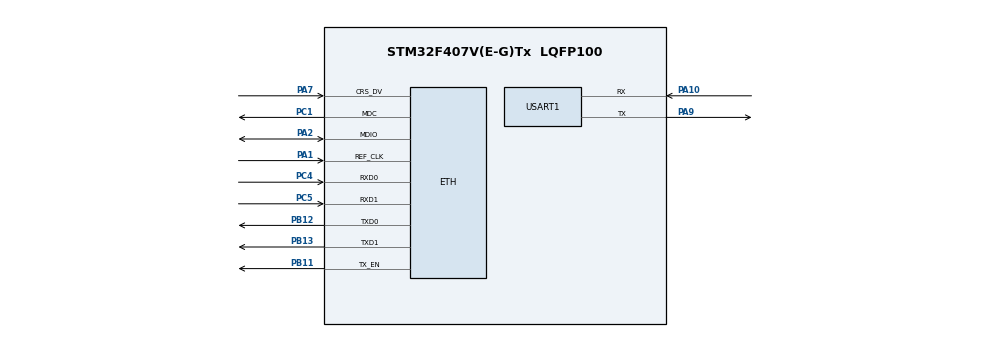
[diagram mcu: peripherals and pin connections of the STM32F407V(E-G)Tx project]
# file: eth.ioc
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ETH.MediaInterface=HAL_ETH_RMII_MODE
FREERTOS.Tasks01=defaultTask,24,128,StartDefaultTask,Default,NULL,Dynamic,NULL,NULL
LWIP.LWIP_HTTPD=1
LWIP.Version=v2.1.2_Cube
Mcu.Family=STM32F4
Mcu.Name=STM32F407V(E-G)Tx
Mcu.Package=LQFP100
NVIC.ETH_IRQn=true\:5\:0\:true\:false\:true\:true\:true\:true\:true
NVIC.PriorityGroup=NVIC_PRIORITYGROUP_4
NVIC.TIM6_DAC_IRQn=true\:15\:0\:false\:false\:true\:false\:false\:true\:true
NVIC.TimeBase=TIM6_DAC_IRQn
NVIC.TimeBaseIP=TIM6
NVIC.USART1_IRQn=true\:5\:0\:false\:false\:true\:true\:true\:true\:true
PA1.Mode=RMII
PA1.Signal=ETH_REF_CLK
PA10.Mode=Asynchronous
PA10.Signal=USART1_RX
PA13.Mode=Serial_Wire
PA13.Signal=SYS_JTMS-SWDIO
PA14.Mode=Serial_Wire
PA14.Signal=SYS_JTCK-SWCLK
PA2.Mode=RMII
PA2.Signal=ETH_MDIO
PA7.Mode=RMII
PA7.Signal=ETH_CRS_DV
PA9.Mode=Asynchronous
PA9.Signal=USART1_TX
PB11.Mode=RMII
PB11.Signal=ETH_TX_EN
PB12.Mode=RMII
PB12.Signal=ETH_TXD0
PB13.Mode=RMII
PB13.Signal=ETH_TXD1
PC1.Mode=RMII
PC1.Signal=ETH_MDC
PC4.Mode=RMII
PC4.Signal=ETH_RXD0
PC5.Mode=RMII
PC5.Signal=ETH_RXD1
PH0-OSC_IN.Mode=HSE-External-Oscillator
PH0-OSC_IN.Signal=RCC_OSC_IN
PH1-OSC_OUT.Mode=HSE-External-Oscillator
PH1-OSC_OUT.Signal=RCC_OSC_OUT
ProjectManager.HeapSize=0x200
ProjectManager.StackSize=0x400
ProjectManager.TargetToolchain=MDK-ARM V5.32
RCC.48MHZClocksFreq_Value=84000000
RCC.AHBFreq_Value=168000000
RCC.APB1CLKDivider=RCC_HCLK_DIV4
RCC.APB1Freq_Value=42000000
RCC.APB1TimFreq_Value=84000000
RCC.APB2CLKDivider=RCC_HCLK_DIV2
RCC.APB2Freq_Value=84000000
RCC.APB2TimFreq_Value=168000000
RCC.CortexFreq_Value=168000000
RCC.HCLKFreq_Value=168000000
RCC.HSE_VALUE=25000000
RCC.HSI_VALUE=16000000
RCC.PLLM=25
RCC.PLLN=336
RCC.PLLSourceVirtual=RCC_PLLSOURCE_HSE
RCC.SYSCLKFreq_VALUE=168000000
RCC.SYSCLKSource=RCC_SYSCLKSOURCE_PLLCLK
RCC.VCOOutputFreq_Value=336000000
USART1.VirtualMode=VM_ASYNC
VP_FREERTOS_VS_CMSIS_V2.Mode=CMSIS_V2
VP_LWIP_VS_Enabled.Mode=Enabled
VP_SYS_VS_tim6.Mode=TIM6
board=custom

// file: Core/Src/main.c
/* USER CODE BEGIN Header */
/**
  ******************************************************************************
  * @file           : main.c
  * @brief          : Main program body
  ******************************************************************************
  * @attention
  *
  * Copyright (c) 2026 STMicroelectronics.
  * All rights reserved.
  *
  * This software is licensed under terms that can be found in the LICENSE file
  * in the root directory of this software component.
  * If no LICENSE file comes with this software, it is provided AS-IS.
  *
  ******************************************************************************
  */
/* USER CODE END Header */
#include "main.h"
#include "cmsis_os.h"
#include "lwip.h"
#include "usart.h"
#include "gpio.h"

/* USER CODE BEGIN Includes */
#include <stdio.h>

/* USER CODE END Includes */

void SystemClock_Config(void);
void MX_FREERTOS_Init(void);

int main(void)
{

  /* MCU Configuration--------------------------------------------------------*/

  /* Reset of all peripherals, Initializes the Flash interface and the Systick. */
  HAL_Init();

  /* Configure the system clock */
  SystemClock_Config();

  /* Initialize all configured peripherals */
  MX_GPIO_Init();
  MX_USART1_UART_Init();

  /* USER CODE BEGIN 2 */
  printf("\r\n=== System Boot ===\r\n");
  printf("[OK] USART1 ready\r\n");
  /* USER CODE END 2 */

  /* Init scheduler */
  osKernelInitialize();

  /* Call init function for freertos objects (in cmsis_os2.c) */
  MX_FREERTOS_Init();

  /* Start scheduler */
  printf("[OK] Starting FreeRTOS kernel...\r\n");
  osKernelStart();

  /* We should never get here as control is now taken by the scheduler */

  /* Infinite loop */
  while (1)
  {

  }
}

void SystemClock_Config(void)
{
  RCC_OscInitTypeDef RCC_OscInitStruct = {0};
  RCC_ClkInitTypeDef RCC_ClkInitStruct = {0};

  /** Configure the main internal regulator output voltage
  */
  __HAL_RCC_PWR_CLK_ENABLE();
  __HAL_PWR_VOLTAGESCALING_CONFIG(PWR_REGULATOR_VOLTAGE_SCALE1);

  /** Initializes the RCC Oscillators according to the specified parameters
  * in the RCC_OscInitTypeDef structure.
  */
  RCC_OscInitStruct.OscillatorType = RCC_OSCILLATORTYPE_HSE;
  RCC_OscInitStruct.HSEState = RCC_HSE_ON;
  RCC_OscInitStruct.PLL.PLLState = RCC_PLL_ON;
  RCC_OscInitStruct.PLL.PLLSource = RCC_PLLSOURCE_HSE;
  RCC_OscInitStruct.PLL.PLLM = 4;
  RCC_OscInitStruct.PLL.PLLN = 168;
  RCC_OscInitStruct.PLL.PLLP = RCC_PLLP_DIV2;
  RCC_OscInitStruct.PLL.PLLQ = 4;
  if (HAL_RCC_OscConfig(&RCC_OscInitStruct) != HAL_OK)
  {
    Error_Handler();
  }

  /** Initializes the CPU, AHB and APB buses clocks
  */
  RCC_ClkInitStruct.ClockType = RCC_CLOCKTYPE_HCLK|RCC_CLOCKTYPE_SYSCLK
                              |RCC_CLOCKTYPE_PCLK1|RCC_CLOCKTYPE_PCLK2;
  RCC_ClkInitStruct.SYSCLKSource = RCC_SYSCLKSOURCE_PLLCLK;
  RCC_ClkInitStruct.AHBCLKDivider = RCC_SYSCLK_DIV1;
  RCC_ClkInitStruct.APB1CLKDivider = RCC_HCLK_DIV4;
  RCC_ClkInitStruct.APB2CLKDivider = RCC_HCLK_DIV2;

  if (HAL_RCC_ClockConfig(&RCC_ClkInitStruct, FLASH_LATENCY_5) != HAL_OK)
  {
    Error_Handler();
  }
}

void HAL_TIM_PeriodElapsedCallback(TIM_HandleTypeDef *htim)
{
  if (htim->Instance == TIM6)
  {
    HAL_IncTick();
  }
}

void Error_Handler(void)
{
  /* USER CODE BEGIN Error_Handler_Debug */
  printf("[ERR] Error_Handler called!\r\n");
  /* User can add his own implementation to report the HAL error return state */
  __disable_irq();
  while (1)
  {
  }
  /* USER CODE END Error_Handler_Debug */
}

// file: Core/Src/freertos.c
/* USER CODE BEGIN Header */
/**
  ******************************************************************************
  * File Name          : freertos.c
  * Description        : Code for freertos applications
  ******************************************************************************
  * @attention
  *
  * Copyright (c) 2026 STMicroelectronics.
  * All rights reserved.
  *
  * This software is licensed under terms that can be found in the LICENSE file
  * in the root directory of this software component.
  * If no LICENSE file comes with this software, it is provided AS-IS.
  *
  ******************************************************************************
  */
/* USER CODE END Header */

#include "FreeRTOS.h"
#include "task.h"
#include "main.h"
#include "cmsis_os.h"

/* USER CODE BEGIN Includes */
#include <stdio.h>
#include "lwip.h"
#include "lwip/dhcp.h"
#include "dns_server.h"
/* USER CODE END Includes */

/* Definitions for defaultTask */
osThreadId_t defaultTaskHandle;
const osThreadAttr_t defaultTask_attributes = {
  .name = "defaultTask",
  .stack_size = 512 * 4,
  .priority = (osPriority_t) osPriorityNormal,
};

void StartDefaultTask(void *argument);

extern struct netif gnetif;
void MX_FREERTOS_Init(void); /* (MISRA C 2004 rule 8.1) */

void MX_FREERTOS_Init(void) {

  /* Create the thread(s) */
  /* creation of defaultTask */
  defaultTaskHandle = osThreadNew(StartDefaultTask, NULL, &defaultTask_attributes);

}

void StartDefaultTask(void *argument)
{
  /* init code for LWIP */
  printf("[OK] Default task started, init LWIP...\r\n");
  MX_LWIP_Init();
  printf("[OK] LWIP init done, waiting for DHCP IP...\r\n");

  /* USER CODE BEGIN StartDefaultTask */
  uint32_t dhcp_timeout = 0;

  /* === Phase 1: Wait for DHCP === */
  for (;;)
  {
    if (netif_is_link_up(&gnetif)) {
        if (dhcp_supplied_address(&gnetif))
        {
          printf("\r\n[DHCP] Success! Network is ready.\r\n");
          printf("[DHCP] IP Address:  %s\r\n", ip4addr_ntoa(netif_ip4_addr(&gnetif)));
          printf("[DHCP] Subnet Mask: %s\r\n", ip4addr_ntoa(netif_ip4_netmask(&gnetif)));
          printf("[DHCP] Gateway:     %s\r\n", ip4addr_ntoa(netif_ip4_gw(&gnetif)));
          printf("[ETH] MAC Address:  %02X:%02X:%02X:%02X:%02X:%02X\r\n",
                 gnetif.hwaddr[0], gnetif.hwaddr[1], gnetif.hwaddr[2],
                 gnetif.hwaddr[3], gnetif.hwaddr[4], gnetif.hwaddr[5]);
          printf("================================================\r\n");
           dns_server_start();
          http_server_start();
          break;
        }
        else
        {
          dhcp_timeout++;
          printf("[DHCP] Waiting... (%ds)\r", (int)(dhcp_timeout * 2));
          if (dhcp_timeout > 30) {
             printf("\r\n[DHCP] Warning: DHCP taking too long, check your server/cable.\r\n");
             dhcp_timeout = 0;
          }
        }
    } else {
        printf("[LINK] Ethernet cable is DISCONNECTED! Please check.\r\n");
    }
    osDelay(2000);
  }

  /* === Phase 2: Network monitoring loop === */
  printf("[NETMON] Network monitor started\r\n");
  for (;;)
  {
    if (!netif_is_link_up(&gnetif))
    {
      printf("[NETMON] Link DOWN, waiting for cable...\r\n");
      while (!netif_is_link_up(&gnetif))
      {
        osDelay(1000);
      }
      printf("[NETMON] Link restored, restarting DHCP...\r\n");
      dhcp_stop(&gnetif);
      dhcp_start(&gnetif);

      uint32_t wait = 0;
      while (!dhcp_supplied_address(&gnetif) && wait < 30)
      {
        osDelay(2000);
        wait++;
      }
      if (dhcp_supplied_address(&gnetif))
      {
        printf("[NETMON] DHCP re-acquired: %s\r\n",
               ip4addr_ntoa(netif_ip4_addr(&gnetif)));
      }
      else
      {
        printf("[NETMON] DHCP timeout after link restore\r\n");
      }
      continue;
    }

    if (!dhcp_supplied_address(&gnetif))
    {
      printf("[NETMON] DHCP lease lost, restarting...\r\n");
      dhcp_stop(&gnetif);
      dhcp_start(&gnetif);
    }

    /* Print status every 60 seconds (6 cycles * 10s) to reduce UART load */
    static uint32_t mon_cycle = 0;
    if (++mon_cycle >= 6)
    {
      printf("[NETMON] OK | IP: %-15s | Link: UP\r\n",
             ip4addr_ntoa(netif_ip4_addr(&gnetif)));
      mon_cycle = 0;
    }

    osDelay(10000);
  }
  /* USER CODE END StartDefaultTask */
}
